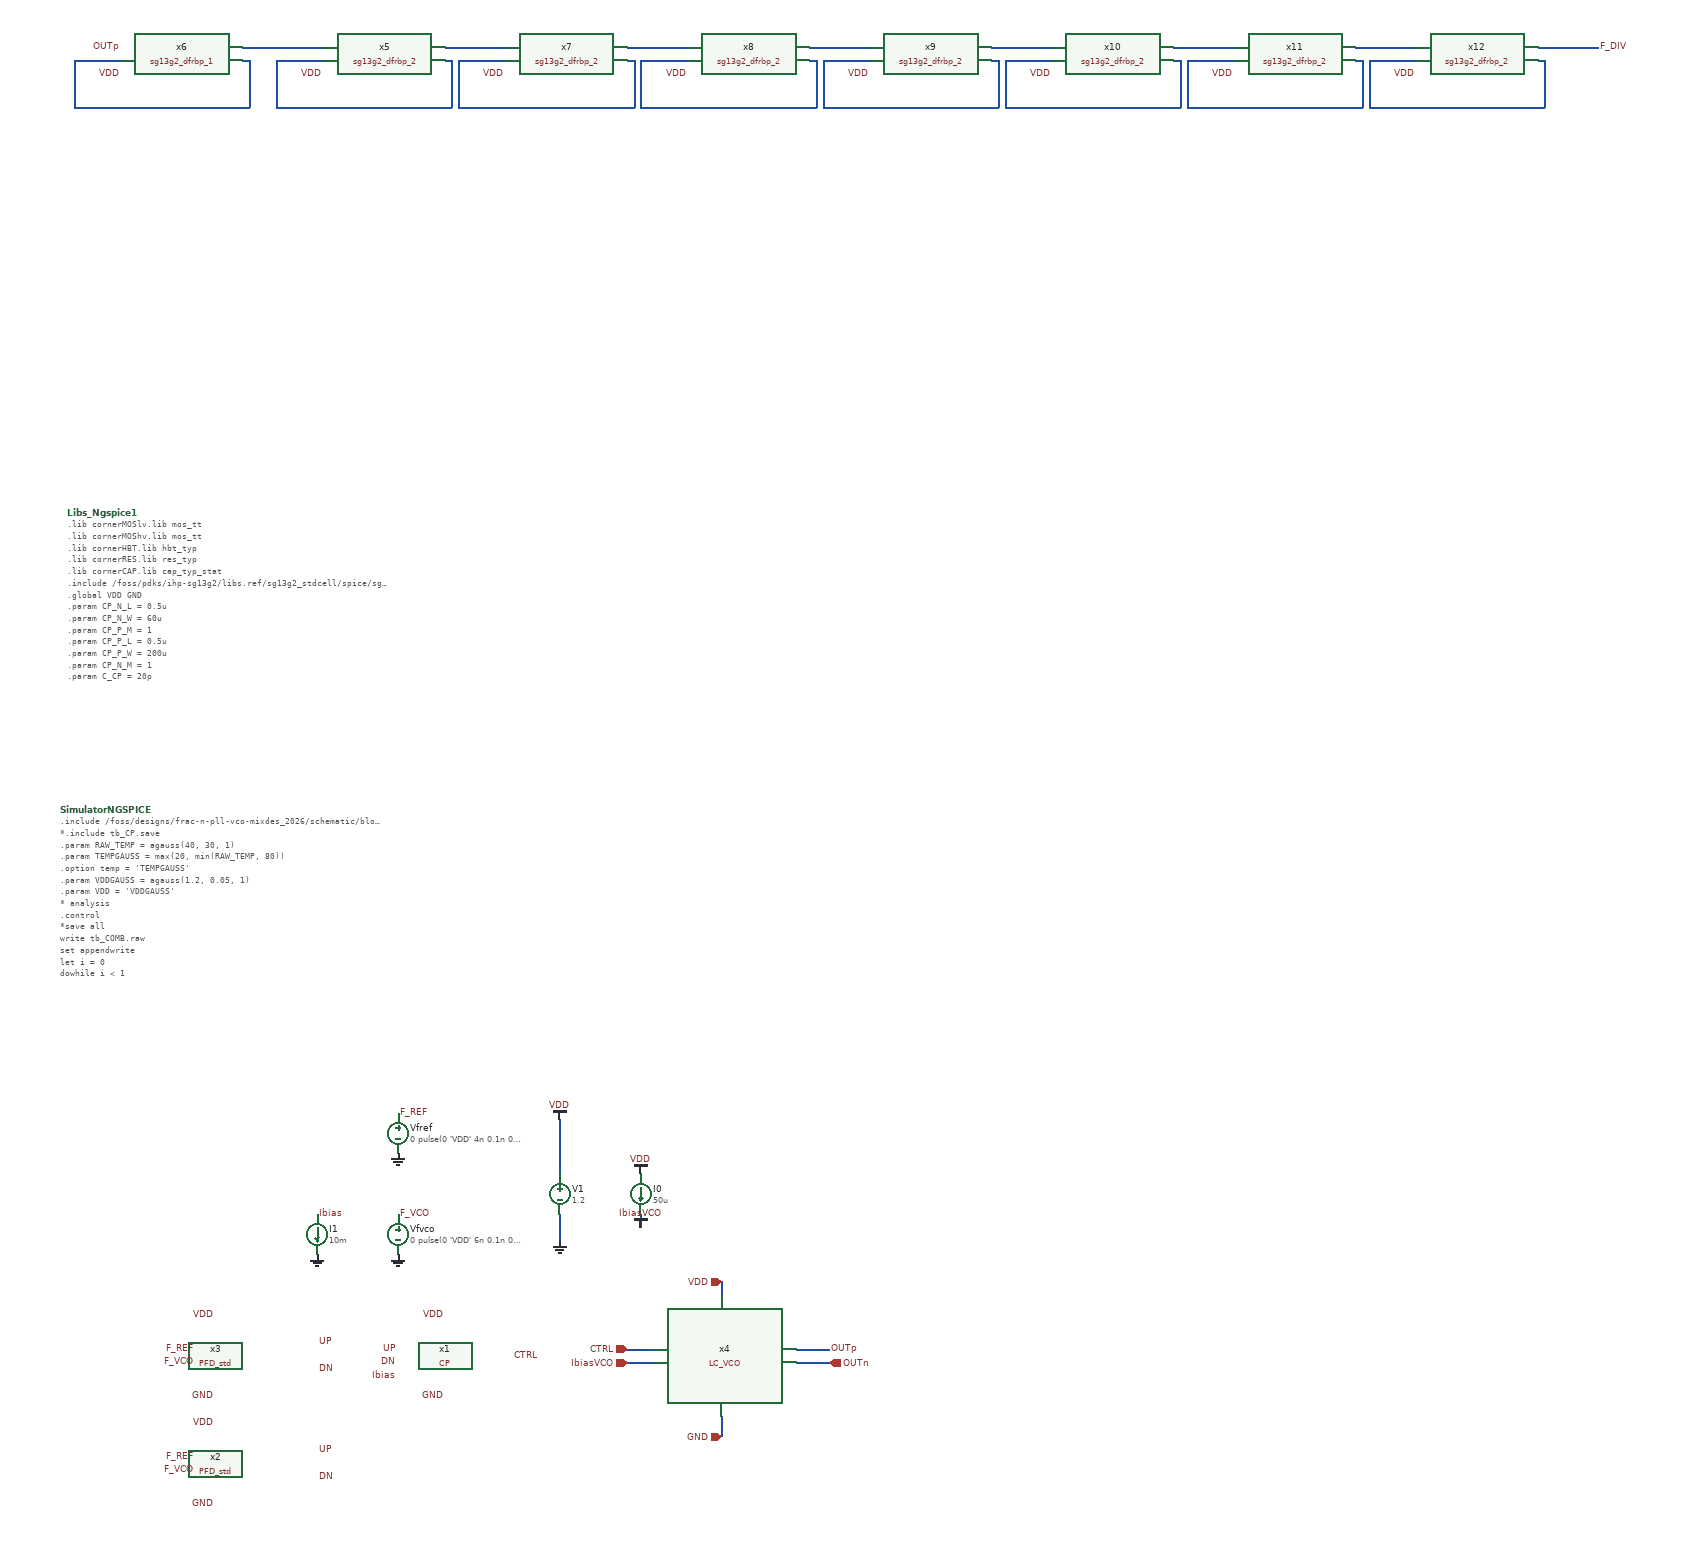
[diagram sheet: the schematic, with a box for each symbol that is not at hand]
v {xschem version=3.4.8RC file_version=1.2}
G {}
K {}
V {}
S {}
F {}
E {}
B 2 1530 -930 2330 -530 {flags=graph
y1=-0.012
y2=1.3
ypos1=0
ypos2=2
divy=5
subdivy=1
unity=1
x1=9.975e-14
x2=1.9999999e-07
divx=5
subdivx=1
xlabmag=1.0
ylabmag=1.0
dataset=-1
unitx=1
logx=0
logy=0
autoload=1
color="5 4"
node="Out;outp
F_DIV"
hilight_wave=-1}
B 2 1530 -1330 2330 -930 {flags=graph
y1=-0.097333465
y2=1.4626665
ypos1=0
ypos2=2
divy=5
subdivy=1
unity=1
x1=9.975e-14
x2=1.9999999e-07
divx=5
subdivx=1
xlabmag=1.0
ylabmag=1.0
dataset=-1
unitx=1
logx=0
logy=0
color="7 8"
node="f_ref
f_vco
"
hilight_wave=-1}
B 2 1530 -1730 2330 -1330 {flags=graph
y1=-0.016
y2=1.3
ypos1=0
ypos2=2
divy=5
subdivy=1
unity=1
x1=9.975e-14
x2=1.9999999e-07
divx=5
subdivx=1
xlabmag=1.0
ylabmag=1.0
dataset=-1
unitx=1
logx=0
logy=0
color="9 10 12"
node="UP;VDD up -
dn
CTRL"
hilight_wave=-1}
B 2 1530 -2130 2330 -1730 {flags=graph
y1=1.0513866
y2=1.2807101
ypos1=0
ypos2=2
divy=5
subdivy=1
unity=1
x1=9.975e-14
x2=1.9999999e-07
divx=5
subdivx=1
xlabmag=1.0
ylabmag=1.0
dataset=-1
unitx=1
logx=0
logy=0
color=11
node="vdd
"}
B 2 1530 -400 2330 0 {flags=graph
y1=-180
y2=-3.9
ypos1=0
ypos2=2
divy=5
subdivy=1
unity=1
x1=-1.3550367e+08
x2=5.3363697e+09
divx=5
subdivx=1
xlabmag=1.0
ylabmag=1.0
dataset=-1
unitx=1
logx=0
logy=0
autoload=1
sim_type=sp
color="5 4"
node="Out;outp db20()
F_DIV;F_DIV db20()"
hilight_wave=-1}
P 4 1 2140 -1610 {}
P 4 1 820 -360 {}
N 870 -690 870 -610 {lab=VDD}
N 870 -550 870 -510 {lab=GND}
N 990 -550 990 -530 {lab=IbiasVCO}
N 1220 -350 1270 -350 {lab=OUTp}
N 1220 -330 1270 -330 {lab=OUTn}
N 970 -350 1010 -350 {lab=CTRL}
N 1110 -250 1110 -220 {lab=GND}
N 970 -330 1010 -330 {lab=IbiasVCO}
N 1110 -450 1110 -430 {lab=VDD}
N 400 -2260 410 -2260 {lab=#net1}
N 410 -2260 410 -2190 {lab=#net1}
N 150 -2190 410 -2190 {lab=#net1}
N 150 -2260 150 -2190 {lab=#net1}
N 150 -2260 220 -2260 {lab=#net1}
N 700 -2260 710 -2260 {lab=#net2}
N 710 -2260 710 -2190 {lab=#net2}
N 450 -2190 710 -2190 {lab=#net2}
N 450 -2260 450 -2190 {lab=#net2}
N 450 -2260 520 -2260 {lab=#net2}
N 400 -2280 520 -2280 {lab=#net3}
N 700 -2280 790 -2280 {lab=#net4}
N 970 -2260 980 -2260 {lab=#net5}
N 980 -2260 980 -2190 {lab=#net5}
N 720 -2190 980 -2190 {lab=#net5}
N 720 -2260 720 -2190 {lab=#net5}
N 720 -2260 790 -2260 {lab=#net5}
N 970 -2280 1060 -2280 {lab=#net6}
N 1240 -2260 1250 -2260 {lab=#net7}
N 1250 -2260 1250 -2190 {lab=#net7}
N 990 -2190 1250 -2190 {lab=#net7}
N 990 -2260 990 -2190 {lab=#net7}
N 990 -2260 1060 -2260 {lab=#net7}
N 1240 -2280 1330 -2280 {lab=#net8}
N 1510 -2260 1520 -2260 {lab=#net9}
N 1520 -2260 1520 -2190 {lab=#net9}
N 1260 -2190 1520 -2190 {lab=#net9}
N 1260 -2260 1260 -2190 {lab=#net9}
N 1260 -2260 1330 -2260 {lab=#net9}
N 1510 -2280 1600 -2280 {lab=#net10}
N 1780 -2260 1790 -2260 {lab=#net11}
N 1790 -2260 1790 -2190 {lab=#net11}
N 1530 -2190 1790 -2190 {lab=#net11}
N 1530 -2260 1530 -2190 {lab=#net11}
N 1530 -2260 1600 -2260 {lab=#net11}
N 1780 -2280 1870 -2280 {lab=#net12}
N 2050 -2260 2060 -2260 {lab=#net13}
N 2060 -2260 2060 -2190 {lab=#net13}
N 1800 -2190 2060 -2190 {lab=#net13}
N 1800 -2260 1800 -2190 {lab=#net13}
N 1800 -2260 1870 -2260 {lab=#net13}
N 2050 -2280 2140 -2280 {lab=#net14}
N 2320 -2260 2330 -2260 {lab=#net15}
N 2330 -2260 2330 -2190 {lab=#net15}
N 2070 -2190 2330 -2190 {lab=#net15}
N 2070 -2260 2070 -2190 {lab=#net15}
N 2070 -2260 2140 -2260 {lab=#net15}
N 2320 -2280 2410 -2280 {lab=F_DIV}
C {title.sym} 160 -30 0 0 {name=l4 author="Rajinthan R"}
C {vsource.sym} 870 -580 0 0 {name=V1 value=1.2 savecurrent=false}
C {gnd.sym} 870 -510 0 0 {name=l1 lab=GND}
C {devices/vdd.sym} 870 -690 0 0 {name=l5 lab=VDD}
C {devices/isource.sym} 990 -580 0 0 {name=I0 value=50u}
C {devices/vdd.sym} 990 -610 0 0 {name=l12 lab=VDD}
C {devices/vdd.sym} 990 -530 2 0 {name=l3 lab=IbiasVCO}
C {vsource.sym} 630 -520 0 0 {name=Vfvco value="0 pulse(0 'VDD' 6n 0.1n 0.1n 5n 10n)" savecurrent=false}
C {lab_pin.sym} 630 -550 0 1 {name=p10 sig_type=std_logic lab=F_VCO}
C {gnd.sym} 630 -490 0 0 {name=l9 lab=GND}
C {vsource.sym} 630 -670 0 0 {name=Vfref value="0 pulse(0 'VDD' 4n 0.1n 0.1n 5n 10n)" savecurrent=false}
C {lab_pin.sym} 630 -700 0 1 {name=p11 sig_type=std_logic lab=F_REF}
C {gnd.sym} 630 -640 0 0 {name=l10 lab=GND}
C {lab_pin.sym} 700 -400 0 0 {name=p8 lab=VDD}
C {lab_pin.sym} 800 -340 0 1 {name=p9 lab=CTRL}
C {lab_pin.sym} 700 -280 0 0 {name=p14 lab=GND}
C {launcher.sym} 1600 -490 0 0 {name=h1
descr="load waves" 
tclcommand="xschem raw_read $netlist_dir/tb_COMB.raw tran
"
}
C {simulator_commands_shown.sym} 130 -1150 0 0 {name=SimulatorNGSPICE
simulator=ngspice
only_toplevel=false 
value="
.include /foss/designs/frac-n-pll-vco-mixdes_2026/schematic/blocks/lc-vco/simulations/IHP_4nH_Inductor.spice
*.include tb_CP.save
.param RAW_TEMP = agauss(40, 30, 1)
.param TEMPGAUSS = max(20, min(RAW_TEMP, 80))
.option temp = 'TEMPGAUSS'
.param VDDGAUSS = agauss(1.2, 0.05, 1)

.param VDD = 'VDDGAUSS'
* analysis

.control
*save all
write tb_COMB.raw
set appendwrite
let i = 0
dowhile i < 1

  
  tran 10p 200n uic
  write tb_COMB.raw
  linearize v(outp)
  fft v(outp)
  write tb_COMB.raw
  fft v(F_DIV)
  write tb_COMB.raw
  let i = i + 1
end
*quit 0
.endc
"}
C {simulator_commands_shown.sym} 140 -1590 0 0 {
name=Libs_Ngspice1
simulator=ngspice
only_toplevel=false
value="
.lib cornerMOSlv.lib mos_tt
.lib cornerMOShv.lib mos_tt
.lib cornerHBT.lib hbt_typ
.lib cornerRES.lib res_typ
.lib cornerCAP.lib cap_typ_stat
.include /foss/pdks/ihp-sg13g2/libs.ref/sg13g2_stdcell/spice/sg13g2_stdcell.spice
.global VDD GND


.param CP_N_L = 0.5u
.param CP_N_W = 60u
.param CP_P_M = 1
.param CP_P_L = 0.5u
.param CP_P_W = 200u
.param CP_N_M = 1
.param C_CP = 20p
"}
C {launcher.sym} 1600 -460 0 0 {name=h4
descr=SimulateNGSPICE
tclcommand="
xschem netlist; 
xschem simulate; 
xschem raw_read $netlist_dir/tb_COMB.raw tran; 
xschem redraw
"}
C {/foss/designs/PLL_IHP_PDK/src/CP.sym} 700 -340 0 0 {name=x1}
C {lab_pin.sym} 510 -550 0 1 {name=p12 sig_type=std_logic lab=Ibias}
C {gnd.sym} 510 -490 0 0 {name=l11 lab=GND}
C {isource.sym} 510 -520 0 0 {name=I1 value=10m}
C {lab_pin.sym} 630 -310 0 0 {name=p13 sig_type=std_logic lab=Ibias}
C {/foss/designs/PLL_IHP_PDK/src/PFD_std.sym} 360 -340 0 0 {name=x3}
C {lab_pin.sym} 360 -400 0 0 {name=p15 lab=VDD}
C {lab_pin.sym} 510 -360 0 1 {name=p16 lab=UP}
C {lab_pin.sym} 330 -350 0 0 {name=p17 lab=F_REF}
C {lab_pin.sym} 330 -330 0 0 {name=p18 lab=F_VCO}
C {lab_pin.sym} 510 -320 0 1 {name=p19 lab=DN}
C {lab_pin.sym} 360 -280 0 0 {name=p20 lab=GND}
C {lab_pin.sym} 630 -350 0 0 {name=p21 lab=UP}
C {lab_pin.sym} 630 -330 0 0 {name=p22 lab=DN}
C {opin.sym} 1270 -330 0 0 {name=p24 lab=OUTn
}
C {iopin.sym} 1110 -450 3 0 {name=p25 lab=VDD
}
C {iopin.sym} 970 -350 2 0 {name=p26 lab=CTRL
}
C {iopin.sym} 1110 -220 1 0 {name=p27 lab=GND
}
C {iopin.sym} 970 -330 2 0 {name=p28 lab=IbiasVCO
}
C {/foss/designs/frac-n-pll-vco-mixdes_2026/schematic/blocks/lc-vco/LC_VCO.sym} 1110 -340 0 0 {name=x4}
C {/foss/designs/PLL_IHP_PDK/src/PFD_std.sym} 360 -180 0 0 {name=x2}
C {lab_pin.sym} 360 -240 0 0 {name=p1 lab=VDD}
C {lab_pin.sym} 510 -200 0 1 {name=p2 lab=UP}
C {lab_pin.sym} 330 -190 0 0 {name=p3 lab=F_REF}
C {lab_pin.sym} 330 -170 0 0 {name=p4 lab=F_VCO}
C {lab_pin.sym} 510 -160 0 1 {name=p5 lab=DN}
C {lab_pin.sym} 360 -120 0 0 {name=p6 lab=GND}
C {sg13g2_stdcells/sg13g2_dfrbp_1.sym} 310 -2260 0 0 {name=x6 VDD=VDD VSS=GND prefix=sg13g2_ }
C {lab_pin.sym} 1270 -350 0 1 {name=p23 lab=OUTp}
C {lab_pin.sym} 220 -2280 0 0 {name=p29 lab=OUTp}
C {sg13g2_stdcells/sg13g2_dfrbp_2.sym} 610 -2260 0 0 {name=x5 VDD=VDD VSS=GND prefix=sg13g2_ }
C {lab_pin.sym} 2410 -2280 0 1 {name=p7 lab=F_DIV}
C {lab_pin.sym} 220 -2240 0 0 {name=p30 lab=VDD}
C {lab_pin.sym} 520 -2240 0 0 {name=p31 lab=VDD}
C {sg13g2_stdcells/sg13g2_dfrbp_2.sym} 880 -2260 0 0 {name=x7 VDD=VDD VSS=GND prefix=sg13g2_ }
C {lab_pin.sym} 790 -2240 0 0 {name=p32 lab=VDD}
C {sg13g2_stdcells/sg13g2_dfrbp_2.sym} 1150 -2260 0 0 {name=x8 VDD=VDD VSS=GND prefix=sg13g2_ }
C {lab_pin.sym} 1060 -2240 0 0 {name=p33 lab=VDD}
C {sg13g2_stdcells/sg13g2_dfrbp_2.sym} 1420 -2260 0 0 {name=x9 VDD=VDD VSS=GND prefix=sg13g2_ }
C {lab_pin.sym} 1330 -2240 0 0 {name=p34 lab=VDD}
C {sg13g2_stdcells/sg13g2_dfrbp_2.sym} 1690 -2260 0 0 {name=x10 VDD=VDD VSS=GND prefix=sg13g2_ }
C {lab_pin.sym} 1600 -2240 0 0 {name=p35 lab=VDD}
C {sg13g2_stdcells/sg13g2_dfrbp_2.sym} 1960 -2260 0 0 {name=x11 VDD=VDD VSS=GND prefix=sg13g2_ }
C {lab_pin.sym} 1870 -2240 0 0 {name=p36 lab=VDD}
C {sg13g2_stdcells/sg13g2_dfrbp_2.sym} 2230 -2260 0 0 {name=x12 VDD=VDD VSS=GND prefix=sg13g2_ }
C {lab_pin.sym} 2140 -2240 0 0 {name=p37 lab=VDD}
